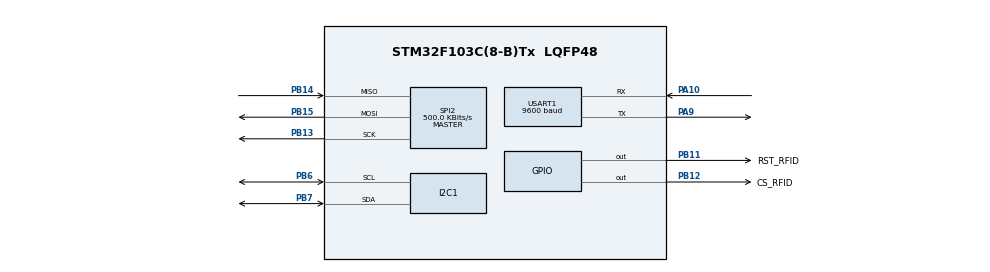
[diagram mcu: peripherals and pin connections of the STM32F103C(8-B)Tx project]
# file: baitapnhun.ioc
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Mcu.Family=STM32F1
Mcu.Name=STM32F103C(8-B)Tx
Mcu.Package=LQFP48
NVIC.PriorityGroup=NVIC_PRIORITYGROUP_4
PA10.Mode=Asynchronous
PA10.Signal=USART1_RX
PA13.Mode=Serial_Wire
PA13.Signal=SYS_JTMS-SWDIO
PA14.Mode=Serial_Wire
PA14.Signal=SYS_JTCK-SWCLK
PA9.Mode=Asynchronous
PA9.Signal=USART1_TX
PB11.GPIO_Label=RST_RFID
PB11.Signal=GPIO_Output
PB12.GPIO_Label=CS_RFID
PB12.Signal=GPIO_Output
PB13.Mode=Full_Duplex_Master
PB13.Signal=SPI2_SCK
PB14.Mode=Full_Duplex_Master
PB14.Signal=SPI2_MISO
PB15.Mode=Full_Duplex_Master
PB15.Signal=SPI2_MOSI
PB6.Mode=I2C
PB6.Signal=I2C1_SCL
PB7.Mode=I2C
PB7.Signal=I2C1_SDA
PD0-OSC_IN.Mode=HSE-External-Oscillator
PD0-OSC_IN.Signal=RCC_OSC_IN
PD1-OSC_OUT.Mode=HSE-External-Oscillator
PD1-OSC_OUT.Signal=RCC_OSC_OUT
ProjectManager.HeapSize=0x200
ProjectManager.StackSize=0x400
ProjectManager.TargetToolchain=MDK-ARM V5.32
RCC.APB1Freq_Value=8000000
RCC.APB2Freq_Value=8000000
SPI2.BaudRatePrescaler=SPI_BAUDRATEPRESCALER_16
SPI2.CalculateBaudRate=500.0 KBits/s
SPI2.Direction=SPI_DIRECTION_2LINES
SPI2.Mode=SPI_MODE_MASTER
SPI2.VirtualType=VM_MASTER
USART1.BaudRate=9600
USART1.VirtualMode=VM_ASYNC
board=custom

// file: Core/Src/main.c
/* USER CODE BEGIN Header */
/**
  ******************************************************************************
  * @file           : main.c
  * @brief          : Main program body
  ******************************************************************************
  * @attention
  *
  * Copyright (c) 2025 STMicroelectronics.
  * All rights reserved.
  *
  * This software is licensed under terms that can be found in the LICENSE file
  * in the root directory of this software component.
  * If no LICENSE file comes with this software, it is provided AS-IS.
  *
  ******************************************************************************
  */
/* USER CODE END Header */
#include "main.h"

/* USER CODE BEGIN Includes */
#include "i2c_lcd.h"
#include "stm32f1_rc522.h"
#include <stdio.h>
#include <string.h>
/* USER CODE END Includes */

I2C_HandleTypeDef hi2c1;

SPI_HandleTypeDef hspi2;

UART_HandleTypeDef huart1;

/* USER CODE BEGIN PV */
I2C_LCD_HandleTypeDef lcd;
uchar cardID[5];
uchar status;
char uart_buffer[50];
uint8_t cardUID[5];
char version_str[16];
/* USER CODE END PV */

void SystemClock_Config(void);
static void MX_GPIO_Init(void);
static void MX_I2C1_Init(void);
static void MX_SPI2_Init(void);
static void MX_USART1_UART_Init(void);
/* USER CODE BEGIN PFP */
void format_card_id_to_string(char *str_buf, uchar *card_id) {
    sprintf(str_buf, "%02X:%02X:%02X:%02X",
            card_id[0], card_id[1], card_id[2], card_id[3]);
}
/* USER CODE END PFP */

/* USER CODE BEGIN 0 */
typedef struct {
    uint8_t uid[4];       // UID
    char student_id[10];  // Ma sinh vien
    char student_name[20]; // Ten sinh vien
} Student;

const Student student_database[] = {
    {{0xBD, 0x8C, 0x45, 0x21}, "11222221", "Nguyen Trung Son"},
    {{0x88, 0x04, 0xB6, 0x3F}, "11222116", "Nguyen Huu Hoan"},
    {{0x49, 0x6A, 0x6C, 0xAB}, "11222194", "Do Trong Phuong"},
		{{0x94, 0xEE, 0xAF, 0xB0}, "00000036", "Bang Phat Suoi"}
};

const int num_students = sizeof(student_database) / sizeof(Student);
/* USER CODE END 0 */

int main(void)
{

  /* MCU Configuration--------------------------------------------------------*/

  /* Reset of all peripherals, Initializes the Flash interface and the Systick. */
  HAL_Init();

  /* Configure the system clock */
  SystemClock_Config();

  /* Initialize all configured peripherals */
  MX_GPIO_Init();
  MX_I2C1_Init();
  MX_SPI2_Init();
  MX_USART1_UART_Init();
  /* USER CODE BEGIN 2 */
  lcd.hi2c = &hi2c1;
  lcd.address = 0x4E;

  lcd_init(&lcd);
  lcd_clear(&lcd);
  lcd_gotoxy(&lcd, 0, 0);
  lcd_puts(&lcd, "HE THONG RFID");
  lcd_gotoxy(&lcd, 0, 1);
  lcd_puts(&lcd, "KHOI DONG...");
  HAL_Delay(1500);

  MFRC522_Init();

	uint8_t version = Read_MFRC522(VersionReg);
  if(version == 0x00 || version == 0xFF){
      lcd_clear(&lcd);
      lcd_gotoxy(&lcd, 0, 0);
      lcd_puts(&lcd, "LOI KET NOI RC522");
      while(1);
  }
	else{
		sprintf(version_str, "0x%02X (v2.0)", version);
		lcd_clear(&lcd);
    lcd_gotoxy(&lcd, 0, 0);
    lcd_puts(&lcd,version_str);
	}
  lcd_clear(&lcd);
  lcd_gotoxy(&lcd, 0, 0);
  lcd_puts(&lcd, "MOI QUET THE!");
  /* USER CODE END 2 */

  /* Infinite loop */
  while (1)
  {

    /* USER CODE BEGIN 3 */
    status = MFRC522_Request(PICC_REQIDL, cardID);
		if (status == MI_OK)
    {
        status = MFRC522_Anticoll(cardID);

        if (status == MI_OK)
        {
            uint8_t found = 0;
            for (int i = 0; i < num_students; i++) {
                if (memcmp(cardID, student_database[i].uid, 4) == 0) {

									sprintf(uart_buffer, "MSV: %s   TEN SV: %s\r\n", student_database[i].student_id, student_database[i].student_name);
                    HAL_UART_Transmit(&huart1, (uint8_t*)uart_buffer, strlen(uart_buffer), 100);

                    lcd_clear(&lcd);
                    lcd_gotoxy(&lcd, 0, 0);
                    lcd_puts(&lcd, (char*)student_database[i].student_name);
                    lcd_gotoxy(&lcd, 0, 1);
                    lcd_puts(&lcd, (char*)student_database[i].student_id);

                  found = 1;
                  break;
                }
            }

            if (!found) {
                sprintf(uart_buffer, "KHONG CO TRONG DANH SACH\r\n");
                HAL_UART_Transmit(&huart1, (uint8_t*)uart_buffer, strlen(uart_buffer), 100);

                lcd_clear(&lcd);
                lcd_gotoxy(&lcd, 0, 0);
                lcd_puts(&lcd, "THE KHONG HOP LE");
            }

            HAL_Delay(2000);

            MFRC522_Halt();
            HAL_Delay(50);

            lcd_clear(&lcd);
            lcd_gotoxy(&lcd, 0, 0);
            lcd_puts(&lcd, "MOI QUET THE!");
        }
    }
    HAL_Delay(100);
  }
  /* USER CODE END 3 */
}

void SystemClock_Config(void)
{
  RCC_OscInitTypeDef RCC_OscInitStruct = {0};
  RCC_ClkInitTypeDef RCC_ClkInitStruct = {0};

  /** Initializes the RCC Oscillators according to the specified parameters
  * in the RCC_OscInitTypeDef structure.
  */
  RCC_OscInitStruct.OscillatorType = RCC_OSCILLATORTYPE_HSI;
  RCC_OscInitStruct.HSIState = RCC_HSI_ON;
  RCC_OscInitStruct.HSICalibrationValue = RCC_HSICALIBRATION_DEFAULT;
  RCC_OscInitStruct.PLL.PLLState = RCC_PLL_NONE;
  if (HAL_RCC_OscConfig(&RCC_OscInitStruct) != HAL_OK)
  {
    Error_Handler();
  }

  /** Initializes the CPU, AHB and APB buses clocks
  */
  RCC_ClkInitStruct.ClockType = RCC_CLOCKTYPE_HCLK|RCC_CLOCKTYPE_SYSCLK
                              |RCC_CLOCKTYPE_PCLK1|RCC_CLOCKTYPE_PCLK2;
  RCC_ClkInitStruct.SYSCLKSource = RCC_SYSCLKSOURCE_HSI;
  RCC_ClkInitStruct.AHBCLKDivider = RCC_SYSCLK_DIV1;
  RCC_ClkInitStruct.APB1CLKDivider = RCC_HCLK_DIV1;
  RCC_ClkInitStruct.APB2CLKDivider = RCC_HCLK_DIV1;

  if (HAL_RCC_ClockConfig(&RCC_ClkInitStruct, FLASH_LATENCY_0) != HAL_OK)
  {
    Error_Handler();
  }
}

static void MX_I2C1_Init(void)
{

  hi2c1.Instance = I2C1;
  hi2c1.Init.ClockSpeed = 100000;
  hi2c1.Init.DutyCycle = I2C_DUTYCYCLE_2;
  hi2c1.Init.OwnAddress1 = 0;
  hi2c1.Init.AddressingMode = I2C_ADDRESSINGMODE_7BIT;
  hi2c1.Init.DualAddressMode = I2C_DUALADDRESS_DISABLE;
  hi2c1.Init.OwnAddress2 = 0;
  hi2c1.Init.GeneralCallMode = I2C_GENERALCALL_DISABLE;
  hi2c1.Init.NoStretchMode = I2C_NOSTRETCH_DISABLE;
  if (HAL_I2C_Init(&hi2c1) != HAL_OK)
  {
    Error_Handler();
  }

}

static void MX_SPI2_Init(void)
{

  /* SPI2 parameter configuration*/
  hspi2.Instance = SPI2;
  hspi2.Init.Mode = SPI_MODE_MASTER;
  hspi2.Init.Direction = SPI_DIRECTION_2LINES;
  hspi2.Init.DataSize = SPI_DATASIZE_8BIT;
  hspi2.Init.CLKPolarity = SPI_POLARITY_LOW;
  hspi2.Init.CLKPhase = SPI_PHASE_1EDGE;
  hspi2.Init.NSS = SPI_NSS_SOFT;
  hspi2.Init.BaudRatePrescaler = SPI_BAUDRATEPRESCALER_16;
  hspi2.Init.FirstBit = SPI_FIRSTBIT_MSB;
  hspi2.Init.TIMode = SPI_TIMODE_DISABLE;
  hspi2.Init.CRCCalculation = SPI_CRCCALCULATION_DISABLE;
  hspi2.Init.CRCPolynomial = 10;
  if (HAL_SPI_Init(&hspi2) != HAL_OK)
  {
    Error_Handler();
  }

}

static void MX_USART1_UART_Init(void)
{

  huart1.Instance = USART1;
  huart1.Init.BaudRate = 9600;
  huart1.Init.WordLength = UART_WORDLENGTH_8B;
  huart1.Init.StopBits = UART_STOPBITS_1;
  huart1.Init.Parity = UART_PARITY_NONE;
  huart1.Init.Mode = UART_MODE_TX_RX;
  huart1.Init.HwFlowCtl = UART_HWCONTROL_NONE;
  huart1.Init.OverSampling = UART_OVERSAMPLING_16;
  if (HAL_UART_Init(&huart1) != HAL_OK)
  {
    Error_Handler();
  }

}

static void MX_GPIO_Init(void)
{
  GPIO_InitTypeDef GPIO_InitStruct = {0};

  /* GPIO Ports Clock Enable */
  __HAL_RCC_GPIOD_CLK_ENABLE();
  __HAL_RCC_GPIOA_CLK_ENABLE();
  __HAL_RCC_GPIOB_CLK_ENABLE();

  /*Configure GPIO pin Output Level */
  HAL_GPIO_WritePin(GPIOA, NG_Pin|OK_Pin, GPIO_PIN_RESET);

  /*Configure GPIO pin Output Level */
  HAL_GPIO_WritePin(GPIOB, RST_RFID_Pin|CS_RFID_Pin, GPIO_PIN_RESET);

  /*Configure GPIO pins : NG_Pin OK_Pin */
  GPIO_InitStruct.Pin = NG_Pin|OK_Pin;
  GPIO_InitStruct.Mode = GPIO_MODE_OUTPUT_PP;
  GPIO_InitStruct.Pull = GPIO_NOPULL;
  GPIO_InitStruct.Speed = GPIO_SPEED_FREQ_LOW;
  HAL_GPIO_Init(GPIOA, &GPIO_InitStruct);

  /*Configure GPIO pins : RST_RFID_Pin CS_RFID_Pin */
  GPIO_InitStruct.Pin = RST_RFID_Pin|CS_RFID_Pin;
  GPIO_InitStruct.Mode = GPIO_MODE_OUTPUT_PP;
  GPIO_InitStruct.Pull = GPIO_NOPULL;
  GPIO_InitStruct.Speed = GPIO_SPEED_FREQ_LOW;
  HAL_GPIO_Init(GPIOB, &GPIO_InitStruct);

}

void Error_Handler(void)
{
  __disable_irq();
  while (1)
  {
  }
}
